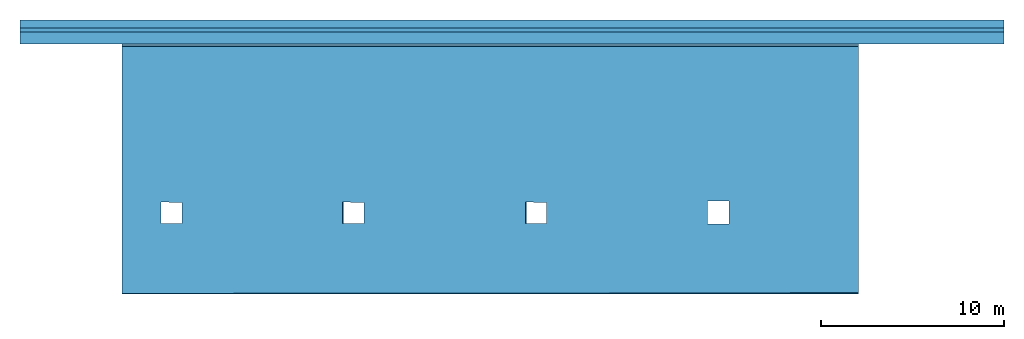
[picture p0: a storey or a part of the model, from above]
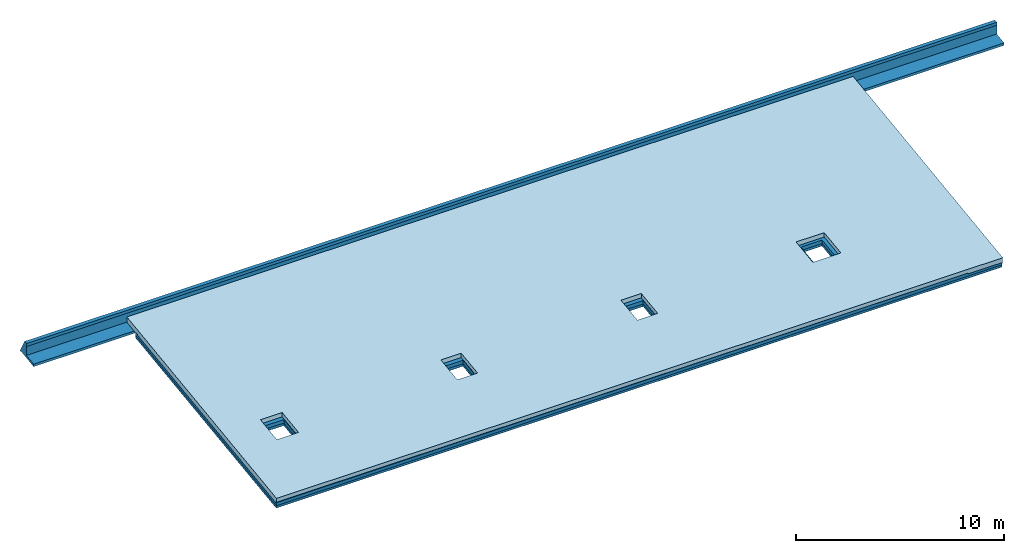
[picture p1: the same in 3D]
Properties of the parts of a building model (IFC2X3)

# File
Description: ViewDefinition [CoordinationView_V2.0], Option [Elements to export: Visible elements (on all stories)], Option [Partial Structure Display: Entire Model], Option [IFC Domain: All], Option [Structural Function: All Elements], Option [Convert Grid elements: On], Option [Convert IFC Annotations and Archicad 2D elements: Off], Option [Convert 2D symbols of Doors and Windows: Off], Option [Export geometries that Participates in Collision Detection only: Off], Option [Split complex elements: Off], Option [Material Preservation: Explode where necessary], Option [Elements in Solid Element Operations: Extruded/revolved], Option [Elements with junctions: Extruded/revolved without junctions], Option [IFC Model position: Survey Point and Project Origin], Option [Curtain Wall export mode: Container Element], Option [Railing export mode: Single Element], Option [Stair export mode: Container Element], Option [Properties To Export: All properties], Option [Space containment: Off], Option [Geometry to type objects: Off], Option [Element Properties: Off], Option [Building Material Properties: Off], Option [Element Parameters: Off], Option [Component Parameters: Off], Option [IFC Base Quantities: Off], Option [Door Window Parameters: Off], Option [IFC Space boundaries: Off], Option [Archicad Zone Categories as IFC Space classification data: Off], Option [Element Classifications: On]
File name: Z:\AFFAIRES\110-2025-ACCORD CADRE PFRA PACA\04-SALLE POLYVALENTE HETZEL (R)\03-PRO-DCE\XX-RENDU\IFC.ifc
Time: 2025-11-09T12:38:07
Author: Architect
Organization: Building Designer Office
Written by: DDS_IFC v3.0
Made in: Graphisoft - Archicad - 28.3.0
Authorization: The authorising person

# IfcProject, Réhabilitation de l'ex atelier-garage en salle polyvalente de la caserne HETZEL à Marseille
Phase: PRO-DCE

# IfcSite, Site
RefLatitude: 48, 52, 0, 0; RefLongitude: 2, 20, 0, 0; RefElevation: 26 m

# IfcBuildingStorey (3)
In: Bâtiment
Name | Elevation (m)
1er étage | 4.85
Rez-de-chaussée | 0
Toiture | 5.4

# IfcBeam: Acrotère HETZEL 1311 x 956, POUTRE-003
In: Toiture
Type - PredefinedType: BEAM
Classification: Poutre (Classification ARCHICAD); Material: Finition ext - Revêtement général
Pset_BeamCommon - Span: 53.9004 m; Slope: 0 deg; IsExternal: no; LoadBearing: yes; Reference: Acrotère HETZEL 1311 x 956
AC_Pset_RenovationAndPhasing - Renovation Status: Existing

# IfcBeam: Aluminium D15 (3)
In: Rez-de-chaussée
Type - PredefinedType: BEAM
Classification: Poutre (Classification ARCHICAD); Material: Aluminium
Pset_BeamCommon - Slope: 0 deg; IsExternal: no; LoadBearing: yes; Reference: Aluminium D15
AC_Pset_RenovationAndPhasing - Renovation Status: New
Name | Span (m)
POUTRE-011 | 1.79414
POUTRE-011 | 3.61094
POUTRE-011 | 1.79576

# IfcBeam: Aluminium D20 (6)
In: Rez-de-chaussée
Type - PredefinedType: BEAM
Classification: Poutre (Classification ARCHICAD); Material: Aluminium
AC_Pset_RenovationAndPhasing - Renovation Status: New
Pset_BeamCommon - Span: 0.00359215 m; Slope: 0 deg; IsExternal: no; LoadBearing: yes; Reference: Aluminium D20

# IfcBeam: Bois massif 35 x 140 (6)
In: Rez-de-chaussée
Type - PredefinedType: BEAM
Classification: Poutre (Classification ARCHICAD); Material: Bois massif
Pset_BeamCommon - Slope: 0 deg; IsExternal: no; LoadBearing: yes; Reference: Bois massif 35 x 140
AC_Pset_RenovationAndPhasing - Renovation Status: New
Name | Span (m)
3 x POUTRE-010 | 4.93
POUTRE-010 | 5
2 x POUTRE-010 | 2.99941

# IfcBeam: Finition ext - Revêtement général 500 x 870, POUTRE-008
In: Rez-de-chaussée
Type - PredefinedType: BEAM
Classification: Poutre (Classification ARCHICAD); Material: Finition ext - Revêtement général
AC_Pset_RenovationAndPhasing - Renovation Status: Existing
Pset_BeamCommon - Span: 7.9827 m; Slope: 0 deg; IsExternal: no; LoadBearing: yes; Reference: Finition ext - Revêtement général 500 x 870

# IfcBeam: Finition ext - Revêtement général 500 x 944, POUTRE-008
In: Rez-de-chaussée
Type - PredefinedType: BEAM
Classification: Poutre (Classification ARCHICAD); Material: Finition ext - Revêtement général
Pset_BeamCommon - Span: 10.4622 m; Slope: 0 deg; IsExternal: no; LoadBearing: yes; Reference: Finition ext - Revêtement général 500 x 944
AC_Pset_RenovationAndPhasing - Renovation Status: Existing

# IfcBeam: GENERIQUE - FINITION INT 70 x 1650 (8)
In: Rez-de-chaussée
Type - PredefinedType: BEAM
Classification: Poutre (Classification ARCHICAD); Material: GENERIQUE - FINITION INT
Pset_BeamCommon - Slope: 7.61 deg; IsExternal: no; LoadBearing: yes; Reference: GENERIQUE - FINITION INT 70 x 1650
AC_Pset_RenovationAndPhasing - Renovation Status: New
Name | Span (m)
2 x POUTRE-006 | 12.1977
4 x POUTRE-006 | 11.3402
2 x POUTRE-006 | 10.4412

# IfcBeam: Poutre HETZEL 454 x 765 (6)
In: Rez-de-chaussée
Type - PredefinedType: BEAM
Classification: Poutre (Classification ARCHICAD); Material: Béton armé (Coulé)
Pset_BeamCommon - Slope: -7.60521 deg; IsExternal: no; LoadBearing: yes; Reference: Poutre HETZEL 454 x 765
AC_Pset_RenovationAndPhasing - Renovation Status: Existing
Name | Span (m)
2 x POUTRE-002 | 13.4677
POUTRE-002 | 13.5676
2 x POUTRE-002 | 13.7819
POUTRE-002 | 13.5683

# IfcBuildingElementPart (156)
Name | In | Material
98 x Finition int - Plaque de plâtre | Rez-de-chaussée | Finition int - Plaque de plâtre
27 x Cloison - Rail 48 | Rez-de-chaussée | Cloison - Rail 48
3 x Isolation - Laine de verre | Rez-de-chaussée | Isolation - Laine de verre
4 x Béton armé (Coulé) | Rez-de-chaussée | Béton armé (Coulé)
4 x Vide d'air | Rez-de-chaussée | Vide d'air
4 x Finition ext - Revêtement général | Rez-de-chaussée | Finition ext - Revêtement général
Béton | Rez-de-chaussée | Béton
Finition int - Enduit plâtre | Rez-de-chaussée | Finition int - Enduit plâtre
7 x Finition int - Plaque de plâtre | 1er étage | Finition int - Plaque de plâtre
4 x Cloison - Rail 48 | 1er étage | Cloison - Rail 48
Finition int - Plaque de plâtre | Toiture | Finition int - Plaque de plâtre
Isolation - Fibres de bois | Toiture | Isolation - Fibres de bois
Béton armé (Coulé) | Toiture | Béton armé (Coulé)

# IfcBuildingElementProxy: IfcBuildingElementProxy (5)
In: Rez-de-chaussée
AC_Pset_RenovationAndPhasing - Renovation Status: New

# IfcBuildingElementProxy: Lavabo 27 (2)
In: Rez-de-chaussée
Classification: Terminal sanitaire (Classification ARCHICAD)
AC_Pset_RenovationAndPhasing - Renovation Status: New

# IfcBuildingElementProxy: Lavabo d'angle 27 (2)
In: Rez-de-chaussée
AC_Pset_RenovationAndPhasing - Renovation Status: New

# IfcBuildingElementProxy: Mop Sink 17, MOBILIER-010
In: Rez-de-chaussée
AC_Pset_RenovationAndPhasing - Renovation Status: New

# IfcBuildingElementProxy: Texte 3D 27 (3)
In: Rez-de-chaussée
Type - ElementType: CONSTRUCTION ELEMENT; PredefinedType: USERDEFINED
Classification: Elément de construction (Classification ARCHICAD)
AC_Pset_RenovationAndPhasing - Renovation Status: New

# IfcBuildingElementProxy: Traitement d'air système divisé 27 (2)
In: Rez-de-chaussée
AC_Pset_RenovationAndPhasing - Renovation Status: New

# IfcBuildingElementProxy: Urinoir 27, MOBILIER-011
In: Rez-de-chaussée
AC_Pset_RenovationAndPhasing - Renovation Status: New

# IfcBuildingElementProxy: Volume - Etude (2)
In: Rez-de-chaussée
Type - ElementType: MORPH; PredefinedType: USERDEFINED
Classification: Forme (Classification ARCHICAD); Material: Volume - Etude
AC_Pset_RenovationAndPhasing - Renovation Status: Existing

# IfcBuildingElementProxy: WC 27 (2)
In: Rez-de-chaussée
AC_Pset_RenovationAndPhasing - Renovation Status: New

# IfcBuildingElementProxy: WC pour handicapés 27 (2)
In: Rez-de-chaussée
AC_Pset_RenovationAndPhasing - Renovation Status: New

# IfcColumn: Bois massif 2 55 x 55 (190)
In: Rez-de-chaussée
Type - PredefinedType: COLUMN
Classification: Poteau (Classification ARCHICAD); Material: Bois massif 2
Pset_ColumnCommon - Slope: 90 deg; IsExternal: yes; LoadBearing: yes; Reference: Bois massif 2 55 x 55
AC_Pset_RenovationAndPhasing - Renovation Status: New

# IfcColumn: Poteau HETZEL 544 x 500 (8)
In: Rez-de-chaussée
Type - PredefinedType: COLUMN
Classification: Poteau (Classification ARCHICAD); Material: Béton armé (Coulé)
Pset_ColumnCommon - Slope: 90 deg; IsExternal: yes; LoadBearing: yes; Reference: Poteau HETZEL 544 x 500
AC_Pset_RenovationAndPhasing - Renovation Status: Existing

# IfcCovering: Tête de mur enveloppée 27, TETE_MUR-007
In: Rez-de-chaussée
Classification: Revêtement (Classification ARCHICAD); Material: Finition ext - Revêtement général
Pset_CoveringCommon - Material: Hachure solide
AC_Pset_RenovationAndPhasing - Renovation Status: New

# IfcDistributionPort (10)
FlowDirection: SOURCEANDSINK
Pset_DistributionPortTypeDuct - ConnectionType: A brides
MEPPortDuct - ProfileShape: Round; Length: 0.001 m
Name | PortNumber | NominalWidth (m) = NominalHeight (m)
2 x Principal 1 | 1 | 0.3
2 x Principal 2 | 2 | 0.3
3 x Principal 1 | 1 | 0.25
3 x Principal 2 | 2 | 0.25

# IfcDoor: Porte 27 (6)
In: Rez-de-chaussée
Type - OperationType: SINGLE_SWING_LEFT; ParameterTakesPrecedence: no; Sizeable: no
Classification: Porte (Classification ARCHICAD)
Pset_DoorCommon - ThermalTransmittance: 0; IsExternal: no
AC_Pset_RenovationAndPhasing - Renovation Status: New
Name | OverallHeight (m) | OverallWidth (m)
PS1 | 2.1 | 1.03
PS2 | 2.1 | 0.9
PB1 | 2.1 | 1.03
PB2 - CF 1H | 2.1 | 1.03
PORTE-004 | 1.82 | 1
PB2 - CF1H | 2.1 | 1.03

# IfcDoor: Porte 27 (6)
In: Rez-de-chaussée
Type - OperationType: SINGLE_SWING_RIGHT; ParameterTakesPrecedence: no; Sizeable: no
Classification: Porte (Classification ARCHICAD)
Pset_DoorCommon - ThermalTransmittance: 0; IsExternal: no
AC_Pset_RenovationAndPhasing - Renovation Status: New
Name | OverallHeight (m) | OverallWidth (m)
PS2 | 2.1 | 0.9
PS1 | 2.1 | 1.03
2 x PB1 | 2.1 | 1.03
PB2 - CF 1H | 2.1 | 1.03
PORTE-004 | 1.82 | 1

# IfcDoor: Porte devanture double, tierce vitrée, imposte 27 (3)
In: Rez-de-chaussée
Type - OperationType: USERDEFINED; ParameterTakesPrecedence: no; Sizeable: no
Classification: Porte (Classification ARCHICAD)
Pset_DoorCommon - ThermalTransmittance: 0; IsExternal: no
AC_Pset_RenovationAndPhasing - Renovation Status: New
Name | OverallHeight (m) | OverallWidth (m) | GlazingAreaFraction
2 x FF2 | 3.83772 | 4.41858 | 5.49054
FF3 | 3.84 | 2.84732 | 9.4365

# IfcDoor: Porte double 27 (2)
In: Rez-de-chaussée
Type - OperationType: DOUBLE_DOOR_SINGLE_SWING; ParameterTakesPrecedence: no; Sizeable: no
OverallHeight: 2.1 m; Classification: Porte (Classification ARCHICAD)
Pset_DoorCommon - ThermalTransmittance: 0; IsExternal: no
Name | OverallWidth (m) | Renovation Status
PORTE-006 | 1.91724 | Existing
CF | 0.6 | New

# IfcDoor: Porte double avec imposte 27 (3)
In: Rez-de-chaussée
Type - OperationType: DOUBLE_DOOR_SINGLE_SWING; ParameterTakesPrecedence: no; Sizeable: no
Classification: Porte (Classification ARCHICAD)
Pset_DoorCommon - ThermalTransmittance: 0; IsExternal: no
AC_Pset_RenovationAndPhasing - Renovation Status: New
Name | OverallHeight (m) | OverallWidth (m) | GlazingAreaFraction
2 x PVi1 - IS 2UP | 2.7 | 1.6 | 3.41144
PM1 | 2.95 | 1.59903 | 1.7445

# IfcFurnishingElement: Kepi+gendarmerie (10)
In: Rez-de-chaussée
Classification: Meuble (Classification ARCHICAD)
AC_Pset_RenovationAndPhasing - Renovation Status: New

# IfcFurnishingElement: Porte-cintres 27 (3)
In: Rez-de-chaussée
Classification: Meuble (Classification ARCHICAD)
AC_Pset_RenovationAndPhasing - Renovation Status: New

# IfcFurnishingElement: Rideau 27 (4)
In: Rez-de-chaussée
Classification: Meuble (Classification ARCHICAD)
AC_Pset_RenovationAndPhasing - Renovation Status: New

# IfcOpeningElement: EMPTY_OPENING (23)
Classification: Percement / Ouverture vide (Classification ARCHICAD)
AC_Pset_RenovationAndPhasing - Renovation Status: Existing
Name | In
TETE_MUR-004 | Rez-de-chaussée
10 x PERCEMENT-006 | Rez-de-chaussée
PERCEMENT-007 | Rez-de-chaussée
PERCEMENT-008 | Rez-de-chaussée
PERCEMENT-009 | 1er étage
4 x PERCEMENT-010 | Toiture
5 x PERCEMENT-002 | Toiture

# IfcRoof: FLAT_ROOF (2)
In: Toiture
Classification: Toiture plate (Classification ARCHICAD)
Pset_RoofCommon - IsExternal: yes
Name | Renovation Status
TOIT-004 | Existing | Material: Herbe
TOIT-004 | New

# IfcSlab: AL - Encoffrement: structure + 1x1 face 61 (4)
Type - PredefinedType: FLOOR
Classification: Dalle de sol (Classification ARCHICAD); Material: Cloison - Rail 48 0.048 m, Finition int - Plaque de plâtre 0.0125 m
Pset_SlabCommon - IsExternal: no; LoadBearing: yes
Name | In | Renovation Status
DALLE-005 | Rez-de-chaussée | Existing
DALLE-005 | Rez-de-chaussée | New
2 x DALLE-005 | 1er étage | New

# IfcSlab: Aluminium 150 (5)
In: Rez-de-chaussée
Type - PredefinedType: FLOOR
Classification: Dalle de sol (Classification ARCHICAD); Material: Aluminium 0.15 m
AC_Pset_RenovationAndPhasing - Renovation Status: New
Pset_SlabCommon - IsExternal: no; LoadBearing: yes

# IfcSlab: Aluminium 1948, DALLE-010
In: Rez-de-chaussée
Type - PredefinedType: FLOOR
Classification: Dalle de sol (Classification ARCHICAD); Material: Aluminium 1.94767 m
Pset_SlabCommon - IsExternal: no; LoadBearing: yes
AC_Pset_RenovationAndPhasing - Renovation Status: New

# IfcSlab: Bois massif 150, DALLE-007
In: Rez-de-chaussée
Type - PredefinedType: FLOOR
Classification: Dalle de sol (Classification ARCHICAD); Material: Bois massif 0.15 m
AC_Pset_RenovationAndPhasing - Renovation Status: Existing
Pset_SlabCommon - IsExternal: no; LoadBearing: yes

# IfcSlab: Bois massif 50, DALLE-006
In: Rez-de-chaussée
Type - PredefinedType: FLOOR
Classification: Dalle de sol (Classification ARCHICAD); Material: Bois massif 0.05 m
AC_Pset_RenovationAndPhasing - Renovation Status: New
Pset_SlabCommon - IsExternal: no; LoadBearing: yes

# IfcSlab: Bois équarri 2 20 (12)
In: Rez-de-chaussée
Type - PredefinedType: FLOOR
Classification: Dalle de sol (Classification ARCHICAD); Material: Bois équarri 2 0.02 m
AC_Pset_RenovationAndPhasing - Renovation Status: New
Pset_SlabCommon - IsExternal: no; LoadBearing: yes

# IfcSlab: Bois équarri 2 30, DALLE-008
In: Rez-de-chaussée
Type - PredefinedType: FLOOR
Classification: Dalle de sol (Classification ARCHICAD); Material: Bois équarri 2 0.03 m
Pset_SlabCommon - IsExternal: no; LoadBearing: yes
AC_Pset_RenovationAndPhasing - Renovation Status: New

# IfcSlab: Bois équarri 2 400, DALLE-008
In: Rez-de-chaussée
Type - PredefinedType: FLOOR
Classification: Dalle de sol (Classification ARCHICAD); Material: Bois équarri 2 0.4 m
AC_Pset_RenovationAndPhasing - Renovation Status: New
Pset_SlabCommon - IsExternal: no; LoadBearing: yes

# IfcSlab: Béton 100, DALLE-009
In: Rez-de-chaussée
Type - PredefinedType: FLOOR
Classification: Dalle de sol (Classification ARCHICAD); Material: Béton 0.1 m
AC_Pset_RenovationAndPhasing - Renovation Status: New
Pset_SlabCommon - IsExternal: no; LoadBearing: yes

# IfcSlab: Béton 1100, DALLE-008
In: Rez-de-chaussée
Type - PredefinedType: FLOOR
Classification: Dalle de sol (Classification ARCHICAD); Material: Béton 1.1 m
Pset_SlabCommon - IsExternal: no; LoadBearing: yes
AC_Pset_RenovationAndPhasing - Renovation Status: Existing

# IfcSlab: Béton 150, DALLE-004
In: Rez-de-chaussée
Type - PredefinedType: FLOOR
Classification: Dalle de sol (Classification ARCHICAD); Material: Béton 0.15 m
AC_Pset_RenovationAndPhasing - Renovation Status: New
Pset_SlabCommon - IsExternal: no; LoadBearing: yes

# IfcSlab: Béton 904, DALLE-007
In: Rez-de-chaussée
Type - PredefinedType: FLOOR
Classification: Dalle de sol (Classification ARCHICAD); Material: Béton 0.903916 m
AC_Pset_RenovationAndPhasing - Renovation Status: Existing
Pset_SlabCommon - IsExternal: no; LoadBearing: yes

# IfcSlab: Béton armé (Coulé) 480, DALLE-003
In: Rez-de-chaussée
Type - PredefinedType: FLOOR
Classification: Dalle de sol (Classification ARCHICAD); Material: Béton armé (Coulé) 0.48 m
AC_Pset_RenovationAndPhasing - Renovation Status: Existing
Pset_SlabCommon - IsExternal: no; LoadBearing: yes

# IfcSlab: Finition int - Faux-plafond 61 (2)
In: 1er étage
Type - PredefinedType: FLOOR
Classification: Dalle de sol (Classification ARCHICAD); Material: Finition int - Faux-plafond 0.0605 m
Pset_SlabCommon - IsExternal: no; LoadBearing: yes
AC_Pset_RenovationAndPhasing - Renovation Status: New

# IfcSlab: GENERIQUE - STRUCTURE 300, DALLE-004
In: Rez-de-chaussée
Type - PredefinedType: FLOOR
Classification: Dalle de sol (Classification ARCHICAD); Material: GENERIQUE - STRUCTURE 0.3 m
AC_Pset_RenovationAndPhasing - Renovation Status: New
Pset_SlabCommon - IsExternal: no; LoadBearing: yes

# IfcSlab: Terre 300, DALLE-005
In: Rez-de-chaussée
Type - PredefinedType: FLOOR
Classification: Dalle de sol (Classification ARCHICAD); Material: Terre 0.3 m
AC_Pset_RenovationAndPhasing - Renovation Status: New
Pset_SlabCommon - IsExternal: no; LoadBearing: yes

# IfcSlab: Vitrage 10 (4)
In: 1er étage
Type - PredefinedType: ROOF
Classification: Coque (Classification ARCHICAD); Material: Vitrage
AC_Pset_RenovationAndPhasing - Renovation Status: Existing
Pset_SlabCommon - IsExternal: yes; LoadBearing: yes

# IfcWall: 1.5 - Mur ext CF: contrecloison + placo + béton 360 (2)
In: Rez-de-chaussée
Type - PredefinedType: ELEMENTEDWALL
Classification: Mur composite (Classification ARCHICAD)
Pset_ConcreteElementGeneral - ConstructionType: Murs porteurs extérieurs
Pset_WallCommon - IsExternal: yes; LoadBearing: yes
AC_Pset_RenovationAndPhasing - Renovation Status: New

# IfcWall: 1.5 - Mur ext: Fondermax + vide + isolant + maçonnerie + placo 681 (2)
In: Rez-de-chaussée
Type - PredefinedType: ELEMENTEDWALL
Classification: Mur composite (Classification ARCHICAD)
Pset_ConcreteElementGeneral - ConstructionType: Murs porteurs extérieurs
Pset_WallCommon - IsExternal: yes; LoadBearing: yes
AC_Pset_RenovationAndPhasing - Renovation Status: New

# IfcWall: 1.5 - Mur ext: placo + isolant + béton PROJET 303, MUR_EXT-007
In: Rez-de-chaussée
Type - PredefinedType: ELEMENTEDWALL
Classification: Mur composite (Classification ARCHICAD)
Pset_ConcreteElementGeneral - ConstructionType: Murs porteurs extérieurs
AC_Pset_RenovationAndPhasing - Renovation Status: New
Pset_WallCommon - IsExternal: yes; LoadBearing: yes

# IfcWall: AL - Cloison: structure + 1x2 faces 74 (5)
In: Rez-de-chaussée
Type - PredefinedType: ELEMENTEDWALL
Classification: Mur composite (Classification ARCHICAD)
Pset_ConcreteElementGeneral - ConstructionType: Murs porteurs extérieurs
AC_Pset_RenovationAndPhasing - Renovation Status: New
Pset_WallCommon - IsExternal: yes; LoadBearing: yes

# IfcWall: AL - Cloison: structure + 2x2 faces 99 (20)
Type - PredefinedType: ELEMENTEDWALL
Classification: Mur composite (Classification ARCHICAD)
Pset_ConcreteElementGeneral - ConstructionType: Murs porteurs extérieurs
AC_Pset_RenovationAndPhasing - Renovation Status: New
Pset_WallCommon - IsExternal: yes; LoadBearing: yes
Name | In
2 x MUR_EXT-008 | Rez-de-chaussée
2 x MUR_EXT-010 | Rez-de-chaussée
2 x MUR_EXT-009 | Rez-de-chaussée
2 x MUR_EXT-015 | Rez-de-chaussée
5 x MUR_EXT-014 | Rez-de-chaussée
MUR_EXT-016 | Rez-de-chaussée
MUR_EXT-018 | Rez-de-chaussée
MUR_EXT-017 | Rez-de-chaussée
MUR_EXT-012 | Rez-de-chaussée
2 x MUR_EXT-011 | Rez-de-chaussée
MUR_EXT-018 | 1er étage

# IfcWall: AL - Encoffrement: structure + 1x1 face 61 (6)
Type - PredefinedType: ELEMENTEDWALL
Classification: Mur composite (Classification ARCHICAD)
Pset_ConcreteElementGeneral - ConstructionType: Murs porteurs extérieurs
AC_Pset_RenovationAndPhasing - Renovation Status: New
Pset_WallCommon - IsExternal: yes; LoadBearing: yes
Name | In
2 x MUR_EXT-015 | Rez-de-chaussée
MUR_EXT-018 | Rez-de-chaussée
3 x MUR_EXT-018 | 1er étage

# IfcWall: Bois équarri 2 30 (7)
In: Rez-de-chaussée
Type - PredefinedType: ELEMENTEDWALL
Classification: Mur composite (Classification ARCHICAD); Material: Bois équarri 2
Pset_ConcreteElementGeneral - ConstructionType: Murs porteurs extérieurs
AC_Pset_RenovationAndPhasing - Renovation Status: New
Pset_WallCommon - IsExternal: yes; LoadBearing: yes

# IfcWall: Béton armé (Coulé) 100, MUR_EXT-007
In: Rez-de-chaussée
Type - PredefinedType: ELEMENTEDWALL
Classification: Mur composite (Classification ARCHICAD); Material: Béton armé (Coulé)
AC_Pset_RenovationAndPhasing - Renovation Status: Existing
Pset_WallCommon - IsExternal: yes; LoadBearing: yes
Pset_ConcreteElementGeneral - ConstructionType: Murs porteurs extérieurs

# IfcWall: Béton armé (Coulé) 300, MUR_EXT-007
In: Rez-de-chaussée
Type - PredefinedType: ELEMENTEDWALL
Classification: Mur composite (Classification ARCHICAD); Material: Béton armé (Coulé)
Pset_ConcreteElementGeneral - ConstructionType: Murs porteurs extérieurs
Pset_WallCommon - IsExternal: yes; LoadBearing: yes
AC_Pset_RenovationAndPhasing - Renovation Status: Existing

# IfcWall: Béton armé (Coulé) 350, MUR_EXT-009
In: Rez-de-chaussée
Type - PredefinedType: ELEMENTEDWALL
Classification: Mur composite (Classification ARCHICAD); Material: Béton armé (Coulé)
AC_Pset_RenovationAndPhasing - Renovation Status: Existing
Pset_WallCommon - IsExternal: yes; LoadBearing: yes
Pset_ConcreteElementGeneral - ConstructionType: Murs porteurs extérieurs

# IfcWall: Béton armé (Coulé) 400, MUR_EXT-007
In: Rez-de-chaussée
Type - PredefinedType: ELEMENTEDWALL
Classification: Mur composite (Classification ARCHICAD); Material: Béton armé (Coulé)
Pset_ConcreteElementGeneral - ConstructionType: Murs porteurs extérieurs
AC_Pset_RenovationAndPhasing - Renovation Status: Existing
Pset_WallCommon - IsExternal: yes; LoadBearing: yes

# IfcWall: GENERIQUE - STRUCTURE 45, MUR_EXT-009
In: Rez-de-chaussée
Type - PredefinedType: ELEMENTEDWALL
Classification: Mur composite (Classification ARCHICAD); Material: GENERIQUE - STRUCTURE
Pset_ConcreteElementGeneral - ConstructionType: Murs porteurs extérieurs
AC_Pset_RenovationAndPhasing - Renovation Status: New
Pset_WallCommon - IsExternal: yes; LoadBearing: yes

# IfcWallStandardCase: 1.5 - Mur ext: Fondermax + vide + isolant + maçonnerie + placo 681, MUR_EXT-006
In: Rez-de-chaussée
Type - PredefinedType: ELEMENTEDWALL
Classification: Mur composite (Classification ARCHICAD); Material: Finition ext - Revêtement général 0.008 m, Vide d'air 0.04 m, Finition ext - Revêtement général 0.04 m, Vide d'air 0.347 m, Béton armé (Coulé) 0.153 m, Isolation - Laine de verre 0.08 m, Finition int - Plaque de plâtre 0.013 m
Pset_ConcreteElementGeneral - ConstructionType: Murs porteurs extérieurs
Pset_WallCommon - IsExternal: yes; LoadBearing: yes
AC_Pset_RenovationAndPhasing - Renovation Status: New

# IfcWallStandardCase: 1.5 - Mur ext: placo + isolant + béton 303, MUR_EXT-007
In: Rez-de-chaussée
Type - PredefinedType: ELEMENTEDWALL
Classification: Mur composite (Classification ARCHICAD); Material: Béton armé (Coulé) 0.21 m, Isolation - Laine de verre 0.08 m, Finition int - Plaque de plâtre 0.013 m
Pset_ConcreteElementGeneral - ConstructionType: Murs porteurs extérieurs
AC_Pset_RenovationAndPhasing - Renovation Status: New
Pset_WallCommon - IsExternal: yes; LoadBearing: yes

# IfcWallStandardCase: 1.5 - Mur ext: placo + isolant + béton PROJET 303, MUR_EXT-007
In: Rez-de-chaussée
Type - PredefinedType: ELEMENTEDWALL
Classification: Mur composite (Classification ARCHICAD); Material: Finition int - Enduit plâtre 0.01 m, Béton 0.2 m, Isolation - Laine de verre 0.08 m, Finition int - Plaque de plâtre 0.013 m
AC_Pset_RenovationAndPhasing - Renovation Status: New
Pset_WallCommon - IsExternal: yes; LoadBearing: yes
Pset_ConcreteElementGeneral - ConstructionType: Murs porteurs extérieurs

# IfcWallStandardCase: AL - Encoffrement: structure + 1x1 face 61 (2)
In: 1er étage
Type - PredefinedType: ELEMENTEDWALL
Classification: Mur composite (Classification ARCHICAD); Material: Cloison - Rail 48 0.048 m, Finition int - Plaque de plâtre 0.0125 m
Pset_WallCommon - IsExternal: yes; LoadBearing: yes
AC_Pset_RenovationAndPhasing - Renovation Status: New
Pset_ConcreteElementGeneral - ConstructionType: Murs porteurs extérieurs

# IfcWallStandardCase: Aluminium 51 (16)
In: Rez-de-chaussée
Type - PredefinedType: ELEMENTEDWALL
Classification: Mur composite (Classification ARCHICAD); Material: Aluminium 0.051 m
AC_Pset_RenovationAndPhasing - Renovation Status: Existing
Pset_WallCommon - IsExternal: yes; LoadBearing: yes
Pset_ConcreteElementGeneral - ConstructionType: Murs porteurs extérieurs

# IfcWallStandardCase: Bois équarri 2 30 (4)
In: Rez-de-chaussée
Type - PredefinedType: ELEMENTEDWALL
Classification: Mur composite (Classification ARCHICAD); Material: Bois équarri 2 0.03 m
Pset_ConcreteElementGeneral - ConstructionType: Murs porteurs extérieurs
AC_Pset_RenovationAndPhasing - Renovation Status: New
Pset_WallCommon - IsExternal: yes; LoadBearing: yes
Name
3 x MUR_EXT-011
MUR_EXT-012

# IfcWallStandardCase: Bois équarri 2 40 (6)
In: Rez-de-chaussée
Type - PredefinedType: ELEMENTEDWALL
Classification: Mur composite (Classification ARCHICAD); Material: Bois équarri 2 0.04 m
Pset_ConcreteElementGeneral - ConstructionType: Murs porteurs extérieurs
AC_Pset_RenovationAndPhasing - Renovation Status: New
Pset_WallCommon - IsExternal: yes; LoadBearing: yes

# IfcWallStandardCase: Béton armé (Coulé) 150, MUR_EXT-009
In: Rez-de-chaussée
Type - PredefinedType: ELEMENTEDWALL
Classification: Mur composite (Classification ARCHICAD); Material: Béton armé (Coulé) 0.15 m
AC_Pset_RenovationAndPhasing - Renovation Status: New
Pset_ConcreteElementGeneral - ConstructionType: Murs porteurs extérieurs
Pset_WallCommon - IsExternal: yes; LoadBearing: yes

# IfcWallStandardCase: Béton armé (Coulé) 154, MUR_EXT-008
In: Rez-de-chaussée
Type - PredefinedType: ELEMENTEDWALL
Classification: Mur composite (Classification ARCHICAD); Material: Béton armé (Coulé) 0.1535 m
Pset_ConcreteElementGeneral - ConstructionType: Murs porteurs extérieurs
AC_Pset_RenovationAndPhasing - Renovation Status: Existing
Pset_WallCommon - IsExternal: yes; LoadBearing: yes

# IfcWallStandardCase: Béton armé (Coulé) 210 (2)
In: Rez-de-chaussée
Type - PredefinedType: ELEMENTEDWALL
Classification: Mur composite (Classification ARCHICAD); Material: Béton armé (Coulé) 0.21 m
Pset_ConcreteElementGeneral - ConstructionType: Murs porteurs extérieurs
Pset_WallCommon - IsExternal: yes; LoadBearing: yes
Name | Renovation Status
MUR_EXT-009 | New
MUR_EXT-007 | Existing

# IfcWallStandardCase: Finition ext - Revêtement général 14 (16)
In: Rez-de-chaussée
Type - PredefinedType: ELEMENTEDWALL
Classification: Mur composite (Classification ARCHICAD); Material: Finition ext - Revêtement général 0.014 m
Pset_ConcreteElementGeneral - ConstructionType: Murs porteurs extérieurs
AC_Pset_RenovationAndPhasing - Renovation Status: Existing
Pset_WallCommon - IsExternal: yes; LoadBearing: yes

# IfcWallStandardCase: Finition ext - Revêtement général 200 (16)
In: Rez-de-chaussée
Type - PredefinedType: ELEMENTEDWALL
Classification: Mur composite (Classification ARCHICAD); Material: Finition ext - Revêtement général 0.2 m
Pset_ConcreteElementGeneral - ConstructionType: Murs porteurs extérieurs
AC_Pset_RenovationAndPhasing - Renovation Status: Existing
Pset_WallCommon - IsExternal: yes; LoadBearing: yes

# IfcWallStandardCase: Finition int - Stratifié 100, MUR_EXT-013
In: Rez-de-chaussée
Type - PredefinedType: ELEMENTEDWALL
Classification: Mur composite (Classification ARCHICAD); Material: Finition int - Stratifié 0.1 m
AC_Pset_RenovationAndPhasing - Renovation Status: New
Pset_ConcreteElementGeneral - ConstructionType: Murs porteurs extérieurs
Pset_WallCommon - IsExternal: yes; LoadBearing: yes

# IfcWallStandardCase: GENERIQUE - FINITION EXT 50 (4)
In: Rez-de-chaussée
Type - PredefinedType: ELEMENTEDWALL
Classification: Mur composite (Classification ARCHICAD); Material: GENERIQUE - FINITION EXT 0.05 m
Pset_ConcreteElementGeneral - ConstructionType: Murs porteurs extérieurs
AC_Pset_RenovationAndPhasing - Renovation Status: New
Pset_WallCommon - IsExternal: yes; LoadBearing: yes
Name
MUR_EXT-010
MUR_EXT-009
MUR_EXT-007
MUR_EXT-008

# IfcWallStandardCase: GENERIQUE - STRUCTURE 300, MUR_EXT-006
In: Rez-de-chaussée
Type - PredefinedType: ELEMENTEDWALL
Classification: Mur composite (Classification ARCHICAD); Material: GENERIQUE - STRUCTURE 0.3 m
Pset_ConcreteElementGeneral - ConstructionType: Murs porteurs extérieurs
AC_Pset_RenovationAndPhasing - Renovation Status: New
Pset_WallCommon - IsExternal: yes; LoadBearing: yes

# IfcWallStandardCase: GENERIQUE - STRUCTURE 50, MUR_EXT-006
In: Rez-de-chaussée
Type - PredefinedType: ELEMENTEDWALL
Classification: Mur composite (Classification ARCHICAD); Material: GENERIQUE - STRUCTURE 0.05 m
Pset_ConcreteElementGeneral - ConstructionType: Murs porteurs extérieurs
AC_Pset_RenovationAndPhasing - Renovation Status: New
Pset_WallCommon - IsExternal: yes; LoadBearing: yes

# IfcWallStandardCase: Vide d'air 50 (2)
In: Rez-de-chaussée
Type - PredefinedType: ELEMENTEDWALL
Classification: Mur composite (Classification ARCHICAD); Material: Vide d'air 0.05 m
Pset_ConcreteElementGeneral - ConstructionType: Murs porteurs extérieurs
AC_Pset_RenovationAndPhasing - Renovation Status: New
Pset_WallCommon - IsExternal: yes; LoadBearing: yes
Name
MUR_EXT-007
MUR_EXT-006

# IfcWindow: Fenêtre 27 (4)
In: Rez-de-chaussée
Type - OperationType: SINGLE_PANEL; ParameterTakesPrecedence: no; Sizeable: no
OverallHeight: 2.95 m; Classification: Fenêtre (Classification ARCHICAD)
Pset_WindowCommon - ThermalTransmittance: 0; IsExternal: yes
AC_Pset_RenovationAndPhasing - Renovation Status: New
Name | OverallWidth (m)
VF1 | 1.52627
VF1 | 1.53144
FENETRE-004 | 0.911508
FENETRE-004 | 0.91128

# IfcWindow: Fenêtre devanture avec imposte 1 27, FF1
In: Rez-de-chaussée
Type - OperationType: DOUBLE_PANEL_HORIZONTAL; ParameterTakesPrecedence: no; Sizeable: no
OverallHeight: 3.84 m; OverallWidth: 0.95 m; Classification: Fenêtre (Classification ARCHICAD)
Pset_WindowCommon - ThermalTransmittance: 0; GlazingAreaFraction: 2.839; IsExternal: yes
AC_Pset_RenovationAndPhasing - Renovation Status: New
Pset_ManufacturerOccurrence - SerialNumber: Sans

# IfcWindow: Fenêtre devanture, 2 fixes latéraux, 2 impostes 27, FFi1
In: Rez-de-chaussée
Type - OperationType: USERDEFINED; ParameterTakesPrecedence: no; Sizeable: no
OverallHeight: 3.84 m; OverallWidth: 4.42 m; Classification: Fenêtre (Classification ARCHICAD)
AC_Pset_RenovationAndPhasing - Renovation Status: New
Pset_WindowCommon - ThermalTransmittance: 0; GlazingAreaFraction: 14.0948; IsExternal: yes
Pset_ManufacturerOccurrence - SerialNumber: Sans

# IfcWindow: Fenêtre ronde 27, RB1
In: Rez-de-chaussée
Type - OperationType: USERDEFINED; ParameterTakesPrecedence: no; Sizeable: no
OverallHeight: 1.2 m; OverallWidth: 1.2 m; Classification: Fenêtre (Classification ARCHICAD)
Pset_WindowCommon - ThermalTransmittance: 0; GlazingAreaFraction: 0.950332; IsExternal: yes
AC_Pset_RenovationAndPhasing - Renovation Status: New
